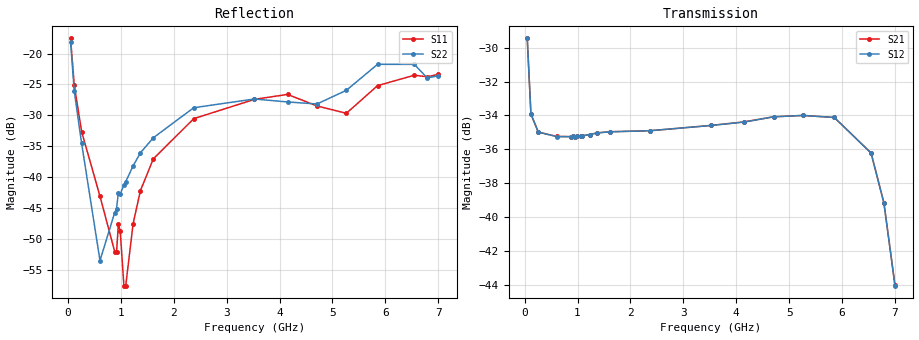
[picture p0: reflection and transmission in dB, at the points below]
! Integrated Device Technology
! Corporate Headquarters
! 6024 Silver Creek Valley Road
! San Jose, CA 95138  USA
! Phone:  1-408-284-8200
! Toll Free:  1-800-223-1366
! Webpage:  http://www.idt.com/
! Timing and RF Division
! 515 Groton Road, Suite 102
! Westford, MA 01886-6024
! Device:  F2258
! Description: Voltage Variable RF Attenuator
! Frequency:  50.0 -  6000.00 MHz
! Package:  3x3 mm Thin QFN Plastic Package: 16 pin
! Ports:  2 RF, 2 DC
!  Pin  1  = NC
!  Pin  2  = NC
!  Pin  3  = RF2  = Port 2
!  Pin  4  = GND
!  Pin  5  = Vdd
!  Pin  6  = NC
!  Pin  7  = VCTRL
!  Pin  8  = NC
!  Pin  9  = GND
!  Pin 10  = RF1  = Port 1
!  Pin 11  = NC
!  Pin 12  = NC
!  Pin 13  = NC
!  Pin 14  = NC
!  Pin 15  = NC
!  Pin 16  = NC
! Vcntrl:  2.110 Volts
! Vdd:  +3.300 Volts
! Current:  1.152 mA
! Data:  The device was measured on a the F2258 evaluation board which has
!  individual transmission lines to the RF pins.  Data was collected
!  using a calibrated network analyzer.  The evaluation board was
!  de-embedded using a TRL calibration technique.
!  The reference plane is the edge of the package pin.
! Misc:  SN 10
!  Action Tracker AT0285
! Date Measured:  2014-12-10
! Date:  2016-01-13  MJV
! Note:
!  Integrated Device Technology supplies this data as a sample of measured
!  data at the package pin for this product.  Your particular data for this
!  product may vary.
!  Data was taken at 25 degrees C.
!  Integrated Device Technology reserves the right to change this data at anytime.
!Freq_(GHz)  S11M_(dB)  S11P_(deg)  S21M_(dB)  S21P_(deg)  S12M_(dB)  S12P_(deg)  S22M_(dB)  S22P_(deg)
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# GHz S dB R 50
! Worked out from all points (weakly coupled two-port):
!   201 points, 50 MHz to 7 GHz, reference 50 ohm
!   highest |S21| = -29.45 dB at 50 MHz (marker M1); lowest = -44.0 dB at 7 GHz (marker M2)
!   lowest |S11| = -57.5 dB at 1.093 GHz (marker M3), VSWR 1.00, Z = 49.9 + j0.114 ohm
!   |S11| at or under -10 dB: start of sweep to end of sweep
!   |S22| runs from -53.5 to -18.1 dB; largest |S21 - S12| = 7e-05
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0.05  -17.55 -111.0  -29.45 -67.7  -29.45 -67.7  -18.11 -110.1
0.1195  -25.12 -106.8  -33.91 -36.4  -33.92 -36.4  -26.09 -101.6
0.2585  -32.62 -111.8  -34.98 -18.6  -34.98 -18.6  -34.51 -97.8
0.606  -43.08 -126.3  -35.24 -10.0  -35.25 -10.0  -53.48 -18.3
0.884  -52.03 166.4  -35.25 -8.5  -35.25 -8.5  -45.70 63.7
0.91875  -52.12 150.0  -35.24 -8.4  -35.24 -8.4  -45.10 64.3
0.9535  -47.59 -162.8  -35.25 -8.3  -35.26 -8.3  -42.48 90.4
0.98825  -48.70 -174.4  -35.24 -8.2  -35.24 -8.2  -42.74 86.8
1.05775  -57.52 154.7  -35.22 -8.1  -35.22 -8.1  -41.20 71.9
1.0925  -57.53 121.0  -35.20 -8.0  -35.20 -8.0  -40.72 69.5
1.2315  -47.52 47.2  -35.13 -8.1  -35.13 -8.1  -38.17 53.3
1.3705  -42.15 37.0  -35.03 -8.6  -35.03 -8.5  -36.04 46.7
1.61375  -37.03 32.8  -34.96 -9.8  -34.97 -9.8  -33.62 38.7
2.37825  -30.53 48.2  -34.90 -13.5  -34.90 -13.5  -28.76 35.0
3.525  -27.41 91.7  -34.59 -20.1  -34.59 -20.1  -27.35 61.3
4.1505  -26.61 104.9  -34.38 -24.6  -34.39 -24.6  -27.83 70.2
4.7065  -28.47 95.6  -34.08 -29.3  -34.08 -29.2  -28.16 52.9
5.2625  -29.66 54.4  -34.00 -35.5  -34.00 -35.4  -25.95 15.5
5.85325  -25.19 29.8  -34.12 -46.0  -34.12 -46.0  -21.74 -6.1
6.54825  -23.51 45.0  -36.21 -66.4  -36.22 -66.5  -21.76 -40.6
6.7915  -23.76 63.3  -39.15 -73.1  -39.18 -73.1  -23.95 -75.8
7  -23.38 84.5  -43.99 -62.0  -44.05 -61.5  -23.59 -129.0
